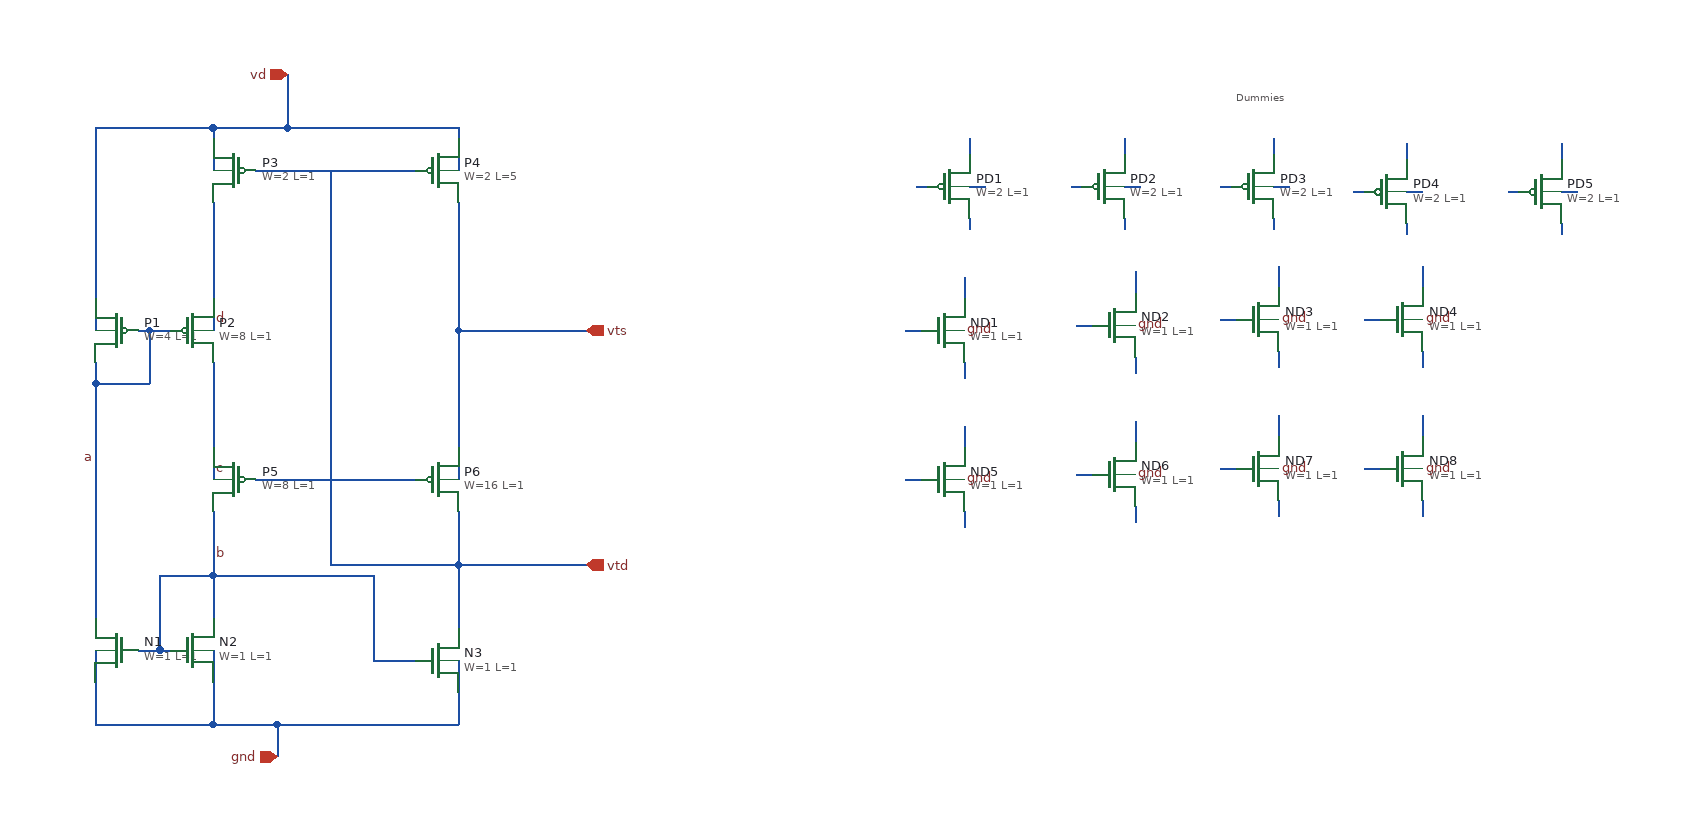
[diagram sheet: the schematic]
v {xschem version=3.1.0 file_version=1.2
}
G {}
K {}
V {}
S {}
E {}
T {Dummies} 860 -340 0 0 0.3 0.3 {}
N -40 260 -40 290 {
lab=gnd}
N -150 190 -140 190 {
lab=b}
N -150 120 -150 190 {
lab=b}
N -150 120 -100 120 {
lab=b}
N -100 120 50 120 {
lab=b}
N 50 120 50 200 {
lab=b}
N 50 200 90 200 {
lab=b}
N -40 260 130 260 {
lab=gnd}
N -160 -110 -140 -110 {
lab=a}
N -100 -300 -30 -300 {
lab=vd}
N -30 -300 130 -300 {
lab=vd}
N 130 110 250 110 {
lab=vtd}
N 130 -110 250 -110 {
lab=vts}
N -40 260 -40 290 {
lab=gnd}
N 10 10 10 110 {
lab=vtd}
N -160 -110 -160 -60 {
lab=a}
N -210 -60 -160 -60 {
lab=a}
N 130 200 130 260 {
lab=gnd}
N -100 190 -100 260 {
lab=gnd}
N -210 190 -210 260 {
lab=gnd}
N -210 -300 -210 -250 {
lab=vd}
N 10 110 130 110 {
lab=vtd}
N 130 110 130 170 {
lab=vtd}
N 130 -120 130 -110 {
lab=vts}
N -100 -140 -100 -110 {
lab=d}
N -210 -60 -210 160 {
lab=a}
N -100 120 -100 160 {
lab=b}
N -210 -80 -210 -60 {
lab=a}
N -210 -190 -210 -110 {
lab=vd}
N -30 -350 -30 -300 {
lab=vd}
N -170 190 -150 190 {
lab=b}
N -210 260 -100 260 {
lab=gnd}
N -210 -300 -100 -300 {
lab=vd}
N -100 260 -40 260 {
lab=gnd}
N -170 -110 -160 -110 {
lab=a}
N -100 100 -100 120 {
lab=b}
N -100 -300 -100 -290 {
lab=vd}
N -60 -260 90 -260 {
lab=vtd}
N 130 -300 130 -290 {
lab=vd}
N 10 -260 10 10 {
lab=vtd}
N -100 -230 -100 -210 {
lab=d}
N -100 -150 -100 -140 {
lab=d}
N 130 -230 130 -180 {
lab=vts}
N 130 -290 130 -260 {
lab=vd}
N -100 -290 -100 -260 {
lab=vd}
N -100 -80 -100 -70 {
lab=c}
N -100 20 -100 30 {
lab=c}
N 130 -110 130 0 {
lab=vts}
N 130 0 130 30 {
lab=vts}
N 130 60 130 110 {
lab=vtd}
N -100 60 -100 100 {
lab=b}
N -100 -10 -100 0 {
lab=c}
N -100 0 -100 20 {
lab=c}
N 10 30 90 30 {
lab=vtd}
N -60 30 10 30 {
lab=vtd}
N -210 -250 -210 -190 {
lab=vd}
N -100 -210 -100 -150 {
lab=d}
N -100 -70 -100 -10 {
lab=c}
N 130 -180 130 -120 {
lab=vts}
N 560 -245 570 -245 {
lab=#net1}
N 610 -245 625 -245 {
lab=#net2}
N 610 -290 610 -275 {
lab=#net3}
N 610 -215 610 -205 {
lab=#net4}
N 705 -245 715 -245 {
lab=#net5}
N 755 -245 770 -245 {
lab=#net6}
N 755 -290 755 -275 {
lab=#net7}
N 755 -215 755 -205 {
lab=#net8}
N 845 -245 855 -245 {
lab=#net9}
N 895 -245 910 -245 {
lab=#net10}
N 895 -290 895 -275 {
lab=#net11}
N 895 -215 895 -205 {
lab=#net12}
N 970 -240 980 -240 {
lab=#net13}
N 1020 -240 1035 -240 {
lab=#net14}
N 1020 -285 1020 -270 {
lab=#net15}
N 1020 -210 1020 -200 {
lab=#net16}
N 1115 -240 1125 -240 {
lab=#net17}
N 1165 -240 1180 -240 {
lab=#net18}
N 1165 -285 1165 -270 {
lab=#net19}
N 1165 -210 1165 -200 {
lab=#net20}
N 550 -110 565 -110 {
lab=#net21}
N 605 -160 605 -140 {
lab=#net22}
N 605 -80 605 -65 {
lab=#net23}
N 710 -115 725 -115 {
lab=#net24}
N 765 -165 765 -145 {
lab=#net25}
N 765 -85 765 -70 {
lab=#net26}
N 845 -120 860 -120 {
lab=#net27}
N 900 -170 900 -150 {
lab=#net28}
N 900 -90 900 -75 {
lab=#net29}
N 980 -120 995 -120 {
lab=#net30}
N 1035 -170 1035 -150 {
lab=#net31}
N 1035 -90 1035 -75 {
lab=#net32}
N 550 30 565 30 {
lab=#net33}
N 605 -20 605 0 {
lab=#net34}
N 605 60 605 75 {
lab=#net35}
N 710 25 725 25 {
lab=#net36}
N 765 -25 765 -5 {
lab=#net37}
N 765 55 765 70 {
lab=#net38}
N 845 20 860 20 {
lab=#net39}
N 900 -30 900 -10 {
lab=#net40}
N 900 50 900 65 {
lab=#net41}
N 980 20 995 20 {
lab=#net42}
N 1035 -30 1035 -10 {
lab=#net43}
N 1035 50 1035 65 {
lab=#net44}
C {devices/iopin.sym} -30 -350 3 0 {name=p1 lab=vd}
C {devices/opin.sym} 250 -110 0 0 {name=p3 lab=vts}
C {devices/opin.sym} 250 110 0 0 {name=p4 lab=vtd}
C {devices/iopin.sym} -40 290 1 0 {name=p2 lab=gnd}
C {devices/lab_pin.sym} -210 10 0 0 {name=l4 sig_type=std_logic lab=a}
C {devices/lab_pin.sym} -100 20 2 0 {name=l6 sig_type=std_logic lab=c}
C {devices/lab_pin.sym} -100 100 2 0 {name=l7 sig_type=std_logic lab=b}
C {devices/lab_pin.sym} -100 -120 2 0 {name=l10 sig_type=std_logic lab=d}
C {sky130_fd_pr/pfet_01v8.sym} -190 -110 0 1 {name=P1
L=1
W=4
nf=2
mult=1
ad="'int((nf+1)/2) * W/nf * 0.29'" 
pd="'2*int((nf+1)/2) * (W/nf + 0.29)'"
as="'int((nf+2)/2) * W/nf * 0.29'" 
ps="'2*int((nf+2)/2) * (W/nf + 0.29)'"
nrd="'0.29 / W'" nrs="'0.29 / W'"
sa=0 sb=0 sd=0
model=pfet_01v8
spiceprefix=X
}
C {sky130_fd_pr/pfet_01v8.sym} -120 -110 0 0 {name=P2
L=1
W=8
nf=4
mult=1
ad="'int((nf+1)/2) * W/nf * 0.29'" 
pd="'2*int((nf+1)/2) * (W/nf + 0.29)'"
as="'int((nf+2)/2) * W/nf * 0.29'" 
ps="'2*int((nf+2)/2) * (W/nf + 0.29)'"
nrd="'0.29 / W'" nrs="'0.29 / W'"
sa=0 sb=0 sd=0
model=pfet_01v8
spiceprefix=X
}
C {sky130_fd_pr/pfet_01v8.sym} -80 -260 0 1 {name=P3
L=1
W=2
nf=1
mult=1
ad="'int((nf+1)/2) * W/nf * 0.29'" 
pd="'2*int((nf+1)/2) * (W/nf + 0.29)'"
as="'int((nf+2)/2) * W/nf * 0.29'" 
ps="'2*int((nf+2)/2) * (W/nf + 0.29)'"
nrd="'0.29 / W'" nrs="'0.29 / W'"
sa=0 sb=0 sd=0
model=pfet_01v8
spiceprefix=X
}
C {sky130_fd_pr/pfet_01v8.sym} 110 -260 0 0 {name=P4
L=5
W=2
nf=1
mult=1
ad="'int((nf+1)/2) * W/nf * 0.29'" 
pd="'2*int((nf+1)/2) * (W/nf + 0.29)'"
as="'int((nf+2)/2) * W/nf * 0.29'" 
ps="'2*int((nf+2)/2) * (W/nf + 0.29)'"
nrd="'0.29 / W'" nrs="'0.29 / W'"
sa=0 sb=0 sd=0
model=pfet_01v8
spiceprefix=X
}
C {sky130_fd_pr/pfet_01v8.sym} -80 30 0 1 {name=P5
L=1
W=8
nf=4
mult=1
ad="'int((nf+1)/2) * W/nf * 0.29'" 
pd="'2*int((nf+1)/2) * (W/nf + 0.29)'"
as="'int((nf+2)/2) * W/nf * 0.29'" 
ps="'2*int((nf+2)/2) * (W/nf + 0.29)'"
nrd="'0.29 / W'" nrs="'0.29 / W'"
sa=0 sb=0 sd=0
model=pfet_01v8
spiceprefix=X
}
C {sky130_fd_pr/pfet_01v8.sym} 110 30 0 0 {name=P6
L=1
W=16
nf=8
mult=1
ad="'int((nf+1)/2) * W/nf * 0.29'" 
pd="'2*int((nf+1)/2) * (W/nf + 0.29)'"
as="'int((nf+2)/2) * W/nf * 0.29'" 
ps="'2*int((nf+2)/2) * (W/nf + 0.29)'"
nrd="'0.29 / W'" nrs="'0.29 / W'"
sa=0 sb=0 sd=0
model=pfet_01v8
spiceprefix=X
}
C {sky130_fd_pr/nfet_01v8.sym} -190 190 0 1 {name=N1
L=1
W=1
nf=1
mult=8
ad="'int((nf+1)/2) * W/nf * 0.29'" 
pd="'2*int((nf+1)/2) * (W/nf + 0.29)'"
as="'int((nf+2)/2) * W/nf * 0.29'" 
ps="'2*int((nf+2)/2) * (W/nf + 0.29)'"
nrd="'0.29 / W'" nrs="'0.29 / W'"
sa=0 sb=0 sd=0
model=nfet_01v8
spiceprefix=X
}
C {sky130_fd_pr/nfet_01v8.sym} -120 190 0 0 {name=N2
L=1
W=1
nf=1
mult=8
ad="'int((nf+1)/2) * W/nf * 0.29'" 
pd="'2*int((nf+1)/2) * (W/nf + 0.29)'"
as="'int((nf+2)/2) * W/nf * 0.29'" 
ps="'2*int((nf+2)/2) * (W/nf + 0.29)'"
nrd="'0.29 / W'" nrs="'0.29 / W'"
sa=0 sb=0 sd=0
model=nfet_01v8
spiceprefix=X
}
C {sky130_fd_pr/nfet_01v8.sym} 110 200 0 0 {name=N3
L=1
W=1
nf=1
mult=8
ad="'int((nf+1)/2) * W/nf * 0.29'" 
pd="'2*int((nf+1)/2) * (W/nf + 0.29)'"
as="'int((nf+2)/2) * W/nf * 0.29'" 
ps="'2*int((nf+2)/2) * (W/nf + 0.29)'"
nrd="'0.29 / W'" nrs="'0.29 / W'"
sa=0 sb=0 sd=0
model=nfet_01v8
spiceprefix=X
}
C {sky130_fd_pr/pfet_01v8.sym} 590 -245 0 0 {name=PD1
L=1
W=2
nf=1
mult=1
ad="'int((nf+1)/2) * W/nf * 0.29'" 
pd="'2*int((nf+1)/2) * (W/nf + 0.29)'"
as="'int((nf+2)/2) * W/nf * 0.29'" 
ps="'2*int((nf+2)/2) * (W/nf + 0.29)'"
nrd="'0.29 / W'" nrs="'0.29 / W'"
sa=0 sb=0 sd=0
model=pfet_01v8
spiceprefix=X
}
C {sky130_fd_pr/pfet_01v8.sym} 735 -245 0 0 {name=PD2
L=1
W=2
nf=1
mult=1
ad="'int((nf+1)/2) * W/nf * 0.29'" 
pd="'2*int((nf+1)/2) * (W/nf + 0.29)'"
as="'int((nf+2)/2) * W/nf * 0.29'" 
ps="'2*int((nf+2)/2) * (W/nf + 0.29)'"
nrd="'0.29 / W'" nrs="'0.29 / W'"
sa=0 sb=0 sd=0
model=pfet_01v8
spiceprefix=X
}
C {sky130_fd_pr/pfet_01v8.sym} 875 -245 0 0 {name=PD3
L=1
W=2
nf=1
mult=1
ad="'int((nf+1)/2) * W/nf * 0.29'" 
pd="'2*int((nf+1)/2) * (W/nf + 0.29)'"
as="'int((nf+2)/2) * W/nf * 0.29'" 
ps="'2*int((nf+2)/2) * (W/nf + 0.29)'"
nrd="'0.29 / W'" nrs="'0.29 / W'"
sa=0 sb=0 sd=0
model=pfet_01v8
spiceprefix=X
}
C {sky130_fd_pr/pfet_01v8.sym} 1000 -240 0 0 {name=PD4
L=1
W=2
nf=1
mult=1
ad="'int((nf+1)/2) * W/nf * 0.29'" 
pd="'2*int((nf+1)/2) * (W/nf + 0.29)'"
as="'int((nf+2)/2) * W/nf * 0.29'" 
ps="'2*int((nf+2)/2) * (W/nf + 0.29)'"
nrd="'0.29 / W'" nrs="'0.29 / W'"
sa=0 sb=0 sd=0
model=pfet_01v8
spiceprefix=X
}
C {sky130_fd_pr/pfet_01v8.sym} 1145 -240 0 0 {name=PD5
L=1
W=2
nf=1
mult=1
ad="'int((nf+1)/2) * W/nf * 0.29'" 
pd="'2*int((nf+1)/2) * (W/nf + 0.29)'"
as="'int((nf+2)/2) * W/nf * 0.29'" 
ps="'2*int((nf+2)/2) * (W/nf + 0.29)'"
nrd="'0.29 / W'" nrs="'0.29 / W'"
sa=0 sb=0 sd=0
model=pfet_01v8
spiceprefix=X
}
C {sky130_fd_pr/nfet_01v8.sym} 585 -110 0 0 {name=ND1
L=1
W=1
nf=1
mult=1
ad="'int((nf+1)/2) * W/nf * 0.29'" 
pd="'2*int((nf+1)/2) * (W/nf + 0.29)'"
as="'int((nf+2)/2) * W/nf * 0.29'" 
ps="'2*int((nf+2)/2) * (W/nf + 0.29)'"
nrd="'0.29 / W'" nrs="'0.29 / W'"
sa=0 sb=0 sd=0
model=nfet_01v8
spiceprefix=X
}
C {sky130_fd_pr/nfet_01v8.sym} 745 -115 0 0 {name=ND2
L=1
W=1
nf=1
mult=1
ad="'int((nf+1)/2) * W/nf * 0.29'" 
pd="'2*int((nf+1)/2) * (W/nf + 0.29)'"
as="'int((nf+2)/2) * W/nf * 0.29'" 
ps="'2*int((nf+2)/2) * (W/nf + 0.29)'"
nrd="'0.29 / W'" nrs="'0.29 / W'"
sa=0 sb=0 sd=0
model=nfet_01v8
spiceprefix=X
}
C {sky130_fd_pr/nfet_01v8.sym} 880 -120 0 0 {name=ND3
L=1
W=1
nf=1
mult=1
ad="'int((nf+1)/2) * W/nf * 0.29'" 
pd="'2*int((nf+1)/2) * (W/nf + 0.29)'"
as="'int((nf+2)/2) * W/nf * 0.29'" 
ps="'2*int((nf+2)/2) * (W/nf + 0.29)'"
nrd="'0.29 / W'" nrs="'0.29 / W'"
sa=0 sb=0 sd=0
model=nfet_01v8
spiceprefix=X
}
C {sky130_fd_pr/nfet_01v8.sym} 1015 -120 0 0 {name=ND4
L=1
W=1
nf=1
mult=1
ad="'int((nf+1)/2) * W/nf * 0.29'" 
pd="'2*int((nf+1)/2) * (W/nf + 0.29)'"
as="'int((nf+2)/2) * W/nf * 0.29'" 
ps="'2*int((nf+2)/2) * (W/nf + 0.29)'"
nrd="'0.29 / W'" nrs="'0.29 / W'"
sa=0 sb=0 sd=0
model=nfet_01v8
spiceprefix=X
}
C {sky130_fd_pr/nfet_01v8.sym} 585 30 0 0 {name=ND5
L=1
W=1
nf=1
mult=1
ad="'int((nf+1)/2) * W/nf * 0.29'" 
pd="'2*int((nf+1)/2) * (W/nf + 0.29)'"
as="'int((nf+2)/2) * W/nf * 0.29'" 
ps="'2*int((nf+2)/2) * (W/nf + 0.29)'"
nrd="'0.29 / W'" nrs="'0.29 / W'"
sa=0 sb=0 sd=0
model=nfet_01v8
spiceprefix=X
}
C {sky130_fd_pr/nfet_01v8.sym} 745 25 0 0 {name=ND6
L=1
W=1
nf=1
mult=1
ad="'int((nf+1)/2) * W/nf * 0.29'" 
pd="'2*int((nf+1)/2) * (W/nf + 0.29)'"
as="'int((nf+2)/2) * W/nf * 0.29'" 
ps="'2*int((nf+2)/2) * (W/nf + 0.29)'"
nrd="'0.29 / W'" nrs="'0.29 / W'"
sa=0 sb=0 sd=0
model=nfet_01v8
spiceprefix=X
}
C {sky130_fd_pr/nfet_01v8.sym} 880 20 0 0 {name=ND7
L=1
W=1
nf=1
mult=1
ad="'int((nf+1)/2) * W/nf * 0.29'" 
pd="'2*int((nf+1)/2) * (W/nf + 0.29)'"
as="'int((nf+2)/2) * W/nf * 0.29'" 
ps="'2*int((nf+2)/2) * (W/nf + 0.29)'"
nrd="'0.29 / W'" nrs="'0.29 / W'"
sa=0 sb=0 sd=0
model=nfet_01v8
spiceprefix=X
}
C {sky130_fd_pr/nfet_01v8.sym} 1015 20 0 0 {name=ND8
L=1
W=1
nf=1
mult=1
ad="'int((nf+1)/2) * W/nf * 0.29'" 
pd="'2*int((nf+1)/2) * (W/nf + 0.29)'"
as="'int((nf+2)/2) * W/nf * 0.29'" 
ps="'2*int((nf+2)/2) * (W/nf + 0.29)'"
nrd="'0.29 / W'" nrs="'0.29 / W'"
sa=0 sb=0 sd=0
model=nfet_01v8
spiceprefix=X
}
C {devices/lab_pin.sym} 605 -110 2 0 {name=l1 sig_type=std_logic lab=gnd}
C {devices/lab_pin.sym} 765 -115 2 0 {name=l2 sig_type=std_logic lab=gnd}
C {devices/lab_pin.sym} 900 -120 2 0 {name=l3 sig_type=std_logic lab=gnd}
C {devices/lab_pin.sym} 1035 -120 2 0 {name=l5 sig_type=std_logic lab=gnd}
C {devices/lab_pin.sym} 1035 20 2 0 {name=l8 sig_type=std_logic lab=gnd}
C {devices/lab_pin.sym} 900 20 2 0 {name=l9 sig_type=std_logic lab=gnd}
C {devices/lab_pin.sym} 765 25 2 0 {name=l11 sig_type=std_logic lab=gnd}
C {devices/lab_pin.sym} 605 30 2 0 {name=l12 sig_type=std_logic lab=gnd}
